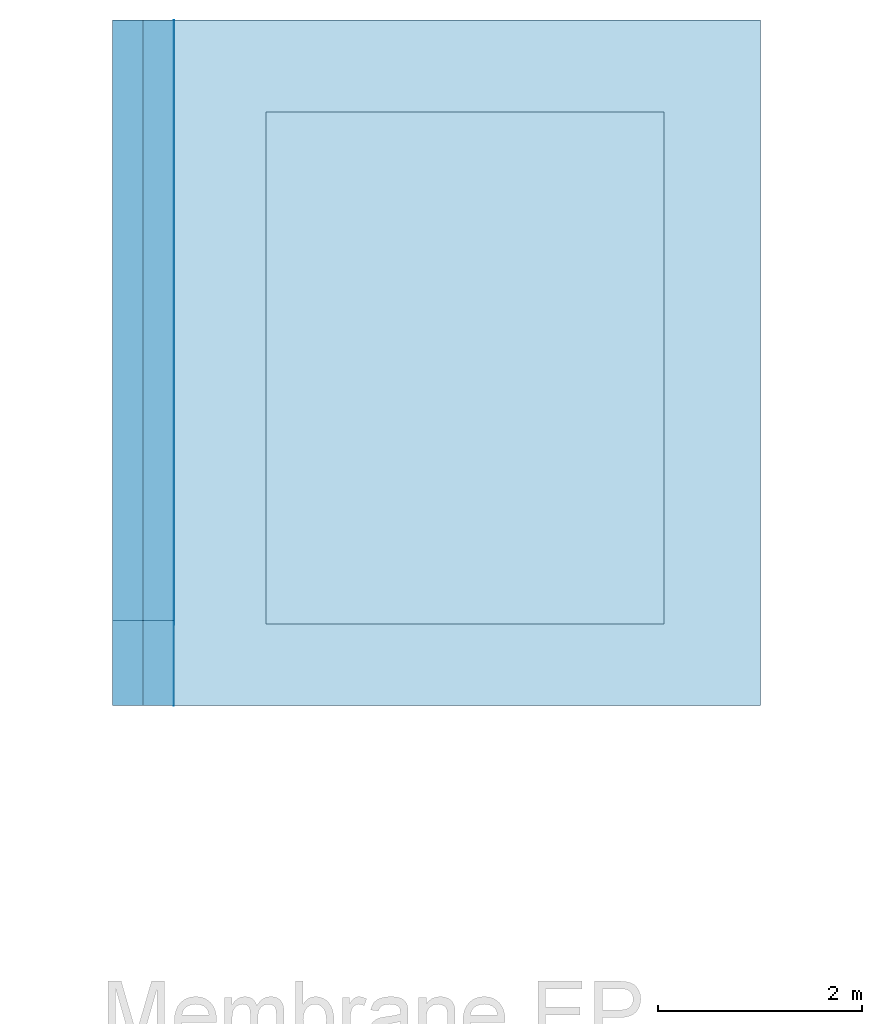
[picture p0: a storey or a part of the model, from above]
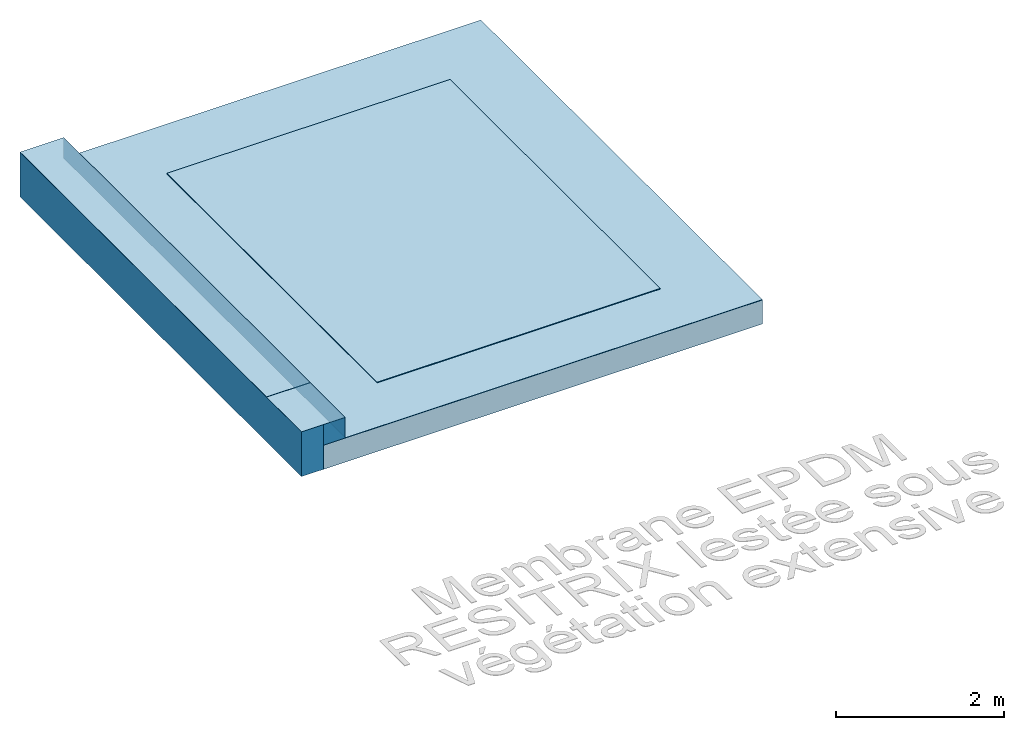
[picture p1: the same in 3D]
Properties of the parts of a building model (IFC2X3)

# File
Description: ViewDefinition [CoordinationView_V2.0]
Time: 2024-08-30T13:14:26
Written by: The EXPRESS Data Manager Version 5.02.0100.07 : 28 Aug 2013
Made in: 22.0.2.392 - Exporter 22.0.2.392 - Interface utilisateur alternative 22.0.2.392
Comment: STEP Physical File produced by: The EXPRESS Data Manager Version 5.02.0100.07 : 28 Aug 2013 * Module: EDMstepFileFactory/EDMstandAlone * Creation date: Fri Aug 30 13:14:26 2024 * Host: VM-BAG-LT-163 * Database: C:\Users\u051572\AppData\Local\Temp\ffd3f7d2-2a03-449f-9b63-6553c8b4547b\1996e1e2-1d6b-484c-acca-05d61731ea74\ifc * Database version: 5507 * Database creation date: Fri Aug 30 13:14:23 2024 * Schema: IFC2X3 * Model: DataRepository.ifc * Model creation date: Fri Aug 30 13:14:23 2024 * Header model: DataRepository.ifc_HeaderModel * Header model creation date: Fri Aug 30 13:14:23 2024 * EDMuser: sdai-user * EDMgroup: sdai-group * License ID and type: 5605 : Permanent license. Expiry date: * EDMstepFileFactory options: 020000

# IfcSite, Default
RefLatitude: 42, 24, 53, 508911; RefLongitude: -71, -15, -29, -58837; RefElevation: 0 mm

# IfcBuilding
Pset_BuildingCommon - NumberOfStoreys: 1

# IfcBuildingStorey: Niveau:Niveau 1, Niveau 1
LongName: Niveau 1; Elevation: 0 mm

# IfcBuildingElementProxy: Texte 3D:Model Text 1, Texte 3D:Model Text 1:35032
In: Niveau 1
Pset_BuildingElementProxyCommon - Reference: Model Text 1; sets with these values: 2

# IfcRoof: Toit de base:Membrane RESITRIX EPDM lestée avec végétation extensive, Toit de base:Membrane RESITRIX EPDM lestée avec végétation extensive:35083
In: Niveau 1
Pset_QuantityTakeOff - Reference: Membrane RESITRIX EPDM lestée avec végétation extensive
Pset_RoofCommon - Reference: Membrane RESITRIX EPDM lestée avec végétation extensive; IsExternal: yes; ProjectedArea: 38.5877 m2; TotalArea: 38.5877 m2

# IfcRoof: Toit de base:Membrane RESITRIX SK W Full bond colléé, Toit de base:Membrane RESITRIX SK W Full bond colléé:35119
In: Niveau 1
Pset_QuantityTakeOff - Reference: Membrane RESITRIX SK W Full bond colléé
Pset_RoofCommon - IsExternal: yes; Reference: Membrane RESITRIX SK W Full bond colléé; ProjectedArea: 3.5474 m2; TotalArea: 3.5474 m2

# IfcRoof: Toit de base:Primer d’adhérence FG35, Toit de base:Primer d’adhérence FG35:35153
In: Niveau 1
Pset_QuantityTakeOff - Reference: Primer d’adhérence FG35
Pset_RoofCommon - IsExternal: yes; Reference: Primer d’adhérence FG35; ProjectedArea: 4.05083 m2; TotalArea: 4.05083 m2

# IfcRoof: Toit de base:Toit 1, Toit de base:Toit 1:35090
In: Niveau 1
Pset_QuantityTakeOff - Reference: Toit 1
Pset_RoofCommon - IsExternal: yes; Reference: Toit 1; ProjectedArea: 40.602 m2; TotalArea: 40.602 m2

# IfcRoof: Toit de base:Végétation, Toit de base:Végétation:35168
In: Niveau 1
Pset_QuantityTakeOff - Reference: Végétation
Pset_RoofCommon - IsExternal: yes; Reference: Végétation; ProjectedArea: 19.5603 m2; TotalArea: 19.5603 m2

# IfcSlab: Toit de base:Membrane RESITRIX EPDM lestée avec végétation extensive, Toit de base:Membrane RESITRIX EPDM lestée avec végétation extensive:35083
In: Niveau 1
Type - PredefinedType: ROOF
Type - Pset_ReinforcementBarPitchOfSlab - Description: Resitrix offre une solution durable pour la couverture de toitures plates. La membrane de finition est composée d’une couche supérieure EPDM armée et d’une sous-couche en SBS revêtue d’un film PE.
Type - Pset_SlabCommon - IsExternal: yes
Material: Membrane Resitrix EPDM lestée avec végétation extensive 2.1 mm, Armature en fibre de verre 1 mm
Pset_QuantityTakeOff - Reference: Membrane RESITRIX EPDM lestée avec végétation extensive
Pset_ReinforcementBarPitchOfSlab - Reference: Membrane RESITRIX EPDM lestée avec végétation extensive
Pset_SlabCommon - Reference: Membrane RESITRIX EPDM lestée avec végétation extensive; PitchAngle: 0 deg

# IfcSlab: Toit de base:Membrane RESITRIX SK W Full bond colléé, Toit de base:Membrane RESITRIX SK W Full bond colléé:35119
In: Niveau 1
Type - PredefinedType: ROOF
Type - Pset_ReinforcementBarPitchOfSlab - Description: Resitrix SK W Full Bond se compose d’une couche supérieure en caoutchouc EPDM armé et d’une sous-couche autocollante en SBS. La membrane est pourvue en-dessous d’un film polyéthylène retirable manuellement.
Type - Pset_SlabCommon - IsExternal: yes
Material: Caoutchouc EPDM SK W Full bond collée 1.5 mm, Armature en fibre de verre 1 mm
Pset_QuantityTakeOff - Reference: Membrane RESITRIX SK W Full bond colléé
Pset_ReinforcementBarPitchOfSlab - Reference: Membrane RESITRIX SK W Full bond colléé
Pset_SlabCommon - PitchAngle: 0 deg; Reference: Membrane RESITRIX SK W Full bond colléé

# IfcSlab: Toit de base:Primer d’adhérence FG35, Toit de base:Primer d’adhérence FG35:35153
In: Niveau 1
Type - PredefinedType: ROOF
Type - Pset_ReinforcementBarPitchOfSlab - Description: Le support (toiture plate) doit être préparé avec le Primer d’adhérence FG35. Le primer d’adhérence permet un collage immédiat et durable. Il faut respecter un temps de séchage de 35 minutes minimum.
Type - Pset_SlabCommon - IsExternal: yes
Material: Primer d’adhérence FG35 0.8 mm
Pset_QuantityTakeOff - Reference: Primer d’adhérence FG35
Pset_ReinforcementBarPitchOfSlab - Reference: Primer d’adhérence FG35
Pset_SlabCommon - PitchAngle: 0 deg; Reference: Primer d’adhérence FG35

# IfcSlab: Toit de base:Toit 1, Toit de base:Toit 1:35090
In: Niveau 1
Type - PredefinedType: ROOF
Type - Pset_SlabCommon - IsExternal: yes
Material: Isolation 100 mm, Pare vapeur 0.8 mm, Béton de pente 50 mm, Structure porteuse 200 mm
Pset_QuantityTakeOff - Reference: Toit 1; sets with these values: 2
Pset_SlabCommon - PitchAngle: 0 deg; Reference: Toit 1

# IfcSlab: Toit de base:Végétation, Toit de base:Végétation:35168
In: Niveau 1
Type - PredefinedType: ROOF
Type - Pset_ReinforcementBarPitchOfSlab - Description: Les toitures végétalisées Resitrix présentent de très nombreux atouts pour lutter contre l’imperméabilisation des sols, réduire les ilots de chaleur ou fixer les particules polluantes mais également pour améliorer le confort des habitants.
Type - Pset_SlabCommon - IsExternal: yes
Material: Végétation extensive 10 mm
Pset_QuantityTakeOff - Reference: Végétation
Pset_ReinforcementBarPitchOfSlab - Reference: Végétation
Pset_SlabCommon - PitchAngle: 0 deg; Reference: Végétation

# IfcWallStandardCase: Mur de base:Membrane RESITRIX SK W EPDM Full bond, Mur de base:Membrane RESITRIX SK W EPDM Full bond:35116
In: Niveau 1
Type - PredefinedType: STANDARD; Material: Caoutchouc EPDM SK W Full bond collée 1.5 mm, Armature en fibre de verre 1 mm
Type - Pset_ReinforcementBarPitchOfWall - Description: La bande d’étanchéité EPDM du relevé est réalisée avec la membrane Resitrix SK W. Elle est placée jusqu’à l’avant du mur et prolongée jusqu’à 100 mm au-delà du coin du relevé par-dessus l’isolation EPDM de la surface du toit (collée). La bande du relevé doit être collée en adhérence totale.
Type - Pset_WallCommon - IsExternal: yes
Pset_QuantityTakeOff - Reference: Membrane RESITRIX SK W EPDM Full bond
Pset_ReinforcementBarPitchOfWall - Reference: Membrane RESITRIX SK W EPDM Full bond
Pset_WallCommon - ExtendToStructure: no; LoadBearing: no; Reference: Membrane RESITRIX SK W EPDM Full bond

# IfcWallStandardCase: Mur de base:Mur 1 (2)
In: Niveau 1
Type - PredefinedType: STANDARD; Material: Isolation 100 mm, Maçonnerie ascendante 200 mm
Type - Pset_WallCommon - IsExternal: yes
Pset_QuantityTakeOff - Reference: Mur 1; sets with these values: 2
Pset_WallCommon - Reference: Mur 1; ExtendToStructure: no; LoadBearing: no
Name (Mur de base:Mur 1:...)
35095
35096

# IfcWallStandardCase: Mur de base:Primer d’adhérence FG35, Mur de base:Primer d’adhérence FG35:35137
In: Niveau 1
Type - PredefinedType: STANDARD; Material: Primer d’adhérence FG35 0.8 mm
Type - Pset_ReinforcementBarPitchOfWall - Description: Le support (toiture plate) doit être préparé avec le Primer d’adhérence FG35. Le primer d’adhérence permet un collage immédiat et durable. Il faut respecter un temps de séchage de 35 minutes minimum.
Type - Pset_WallCommon - IsExternal: yes
Pset_QuantityTakeOff - Reference: Primer d’adhérence FG35
Pset_ReinforcementBarPitchOfWall - Reference: Primer d’adhérence FG35
Pset_WallCommon - ExtendToStructure: no; LoadBearing: no; Reference: Primer d’adhérence FG35
